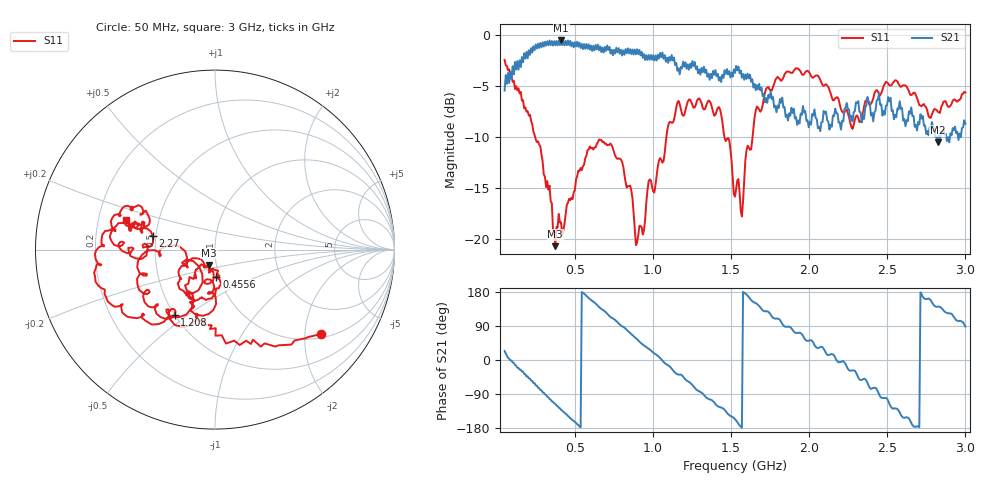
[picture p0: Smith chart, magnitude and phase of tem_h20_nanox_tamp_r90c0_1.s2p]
! nanovna_capture.py 2026-10-26T21:18:01+0900
! NanoVNA-F_V2 fw 0.6.0 SN 4A3639384505514B
! cal: load open short thru cal'ed  over 50000000-3000000000 Hz, 201 points
! points 401, avg 4
! TEM h=20, tampered Nano X, flat back down, 90 deg (length along cell, USB toward PORT 1), centred
# HZ S RI R 50
! S12 and S22 are not measured (written as 0)
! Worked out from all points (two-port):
!   401 points, 50 MHz to 3 GHz, reference 50 ohm
!   highest |S21| = -0.52 dB at 411.4 MHz (marker M1); lowest = -10.5 dB at 2.823 GHz (marker M2)
!   |S21| within 3 dB of the highest: 110.9 MHz to 1.167 GHz (1.056 GHz wide, 165 % of centre); 1.174 GHz to 1.287 GHz (112.3 MHz wide, 9.13 % of centre) (the widest 2 of 14)
!   lowest |S11| = -20.7 dB at 374.5 MHz (marker M3), VSWR 1.20, Z = 46.1 - j8.03 ohm
!   |S11| at or under -10 dB: 245.8 MHz to 1.086 GHz (839.8 MHz wide, 126 % of centre); 1.458 GHz to 1.637 GHz (179.6 MHz wide, 11.6 % of centre)
!   S12 and S22 are empty: the file has one direction only
!   S11 on the Smith chart (normalised r, x): 50 MHz: 1.11, -2.43; 455.6 MHz: 0.97, -0.30; 1.208 GHz: 0.50, -0.45; 2.27 GHz: 0.48, +0.08; 3 GHz: 0.32, +0.14
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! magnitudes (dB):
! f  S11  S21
! 50 MHz  -2.4  -5.4
! 271.2 MHz  -10.7  -1.3
! 374.5 MHz  -20.7  -1.0
! 411.4 MHz  -18.4  -0.5
! 455.6 MHz  -16.4  -0.5
! 544.1 MHz  -13.2  -0.9
! 728.5 MHz  -10.6  -1.8
! 853.9 MHz  -14.7  -1.4
! 898.1 MHz  -20.3  -1.4
! 1.038 GHz  -12.3  -2.3
! 1.156 GHz  -6.6  -3.5
! 1.208 GHz  -7.3  -2.7
! 1.422 GHz  -7.0  -4.5
! 1.525 GHz  -15.8  -3.7
! 1.569 GHz  -17.8  -4.2
! 1.658 GHz  -7.4  -5.4
! 1.732 GHz  -5.1  -6.6
! 2.019 GHz  -4.1  -7.7
! 2.27 GHz  -9.0  -7.9
! 2.513 GHz  -4.9  -6.5
! 2.823 GHz  -7.5  -10.5
! 3 GHz  -5.6  -8.7
